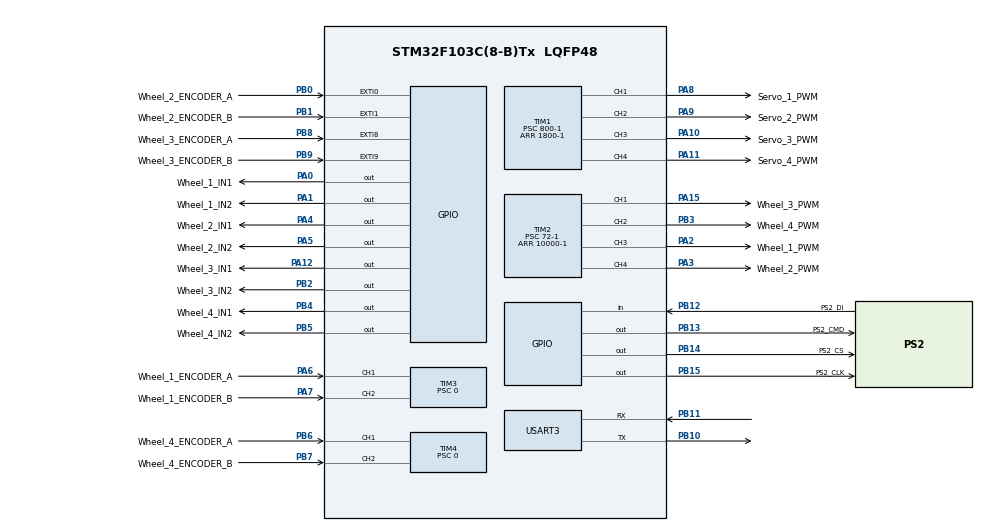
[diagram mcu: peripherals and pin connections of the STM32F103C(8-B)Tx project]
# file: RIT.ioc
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Dma.Request0=USART3_RX
Dma.Request1=USART3_TX
Dma.USART3_RX.0.Direction=DMA_PERIPH_TO_MEMORY
Dma.USART3_RX.0.Instance=DMA1_Channel3
Dma.USART3_RX.0.MemDataAlignment=DMA_MDATAALIGN_BYTE
Dma.USART3_RX.0.MemInc=DMA_MINC_ENABLE
Dma.USART3_RX.0.Mode=DMA_NORMAL
Dma.USART3_RX.0.PeriphDataAlignment=DMA_PDATAALIGN_BYTE
Dma.USART3_RX.0.PeriphInc=DMA_PINC_DISABLE
Dma.USART3_RX.0.Priority=DMA_PRIORITY_LOW
Dma.USART3_TX.1.Direction=DMA_MEMORY_TO_PERIPH
Dma.USART3_TX.1.Instance=DMA1_Channel2
Dma.USART3_TX.1.MemDataAlignment=DMA_MDATAALIGN_BYTE
Dma.USART3_TX.1.MemInc=DMA_MINC_ENABLE
Dma.USART3_TX.1.Mode=DMA_NORMAL
Dma.USART3_TX.1.PeriphDataAlignment=DMA_PDATAALIGN_BYTE
Dma.USART3_TX.1.PeriphInc=DMA_PINC_DISABLE
Dma.USART3_TX.1.Priority=DMA_PRIORITY_LOW
Mcu.Family=STM32F1
Mcu.Name=STM32F103C(8-B)Tx
Mcu.Package=LQFP48
NVIC.DMA1_Channel2_IRQn=true\:0\:0\:false\:false\:true\:false\:true\:true
NVIC.DMA1_Channel3_IRQn=true\:0\:0\:false\:false\:true\:false\:true\:true
NVIC.EXTI0_IRQn=true\:0\:0\:false\:false\:true\:true\:true\:true
NVIC.EXTI1_IRQn=true\:0\:0\:false\:false\:true\:true\:true\:true
NVIC.EXTI9_5_IRQn=true\:0\:0\:false\:false\:true\:true\:true\:true
NVIC.PriorityGroup=NVIC_PRIORITYGROUP_4
NVIC.TIM3_IRQn=true\:0\:0\:false\:false\:true\:true\:true\:true
NVIC.TIM4_IRQn=true\:0\:0\:false\:false\:true\:true\:true\:true
NVIC.USART3_IRQn=true\:0\:0\:false\:false\:true\:true\:true\:true
PA0-WKUP.GPIO_Label=Wheel_1_IN1
PA0-WKUP.Signal=GPIO_Output
PA1.GPIO_Label=Wheel_1_IN2
PA1.Signal=GPIO_Output
PA10.GPIO_Label=Servo_3_PWM
PA10.Signal=S_TIM1_CH3
PA11.GPIO_Label=Servo_4_PWM
PA11.Signal=S_TIM1_CH4
PA12.GPIO_Label=Wheel_3_IN1
PA12.Signal=GPIO_Output
PA13.Mode=Serial_Wire
PA13.Signal=SYS_JTMS-SWDIO
PA14.Mode=Serial_Wire
PA14.Signal=SYS_JTCK-SWCLK
PA15.GPIO_Label=Wheel_3_PWM
PA15.Signal=S_TIM2_CH1_ETR
PA2.GPIO_Label=Wheel_1_PWM
PA2.Signal=S_TIM2_CH3
PA3.GPIO_Label=Wheel_2_PWM
PA3.Signal=S_TIM2_CH4
PA4.GPIO_Label=Wheel_2_IN1
PA4.Signal=GPIO_Output
PA5.GPIO_Label=Wheel_2_IN2
PA5.Signal=GPIO_Output
PA6.GPIO_Label=Wheel_1_ENCODER_A
PA6.GPIO_PuPd=GPIO_PULLUP
PA6.Signal=S_TIM3_CH1
PA7.GPIO_Label=Wheel_1_ENCODER_B
PA7.GPIO_PuPd=GPIO_PULLUP
PA7.Signal=S_TIM3_CH2
PA8.GPIO_Label=Servo_1_PWM
PA8.Signal=S_TIM1_CH1
PA9.GPIO_Label=Servo_2_PWM
PA9.Signal=S_TIM1_CH2
PB0.GPIO_Label=Wheel_2_ENCODER_A
PB0.GPIO_ModeDefaultEXTI=GPIO_MODE_IT_RISING_FALLING
PB0.GPIO_PuPd=GPIO_PULLDOWN
PB0.Signal=GPXTI0
PB1.GPIO_Label=Wheel_2_ENCODER_B
PB1.GPIO_ModeDefaultEXTI=GPIO_MODE_IT_RISING_FALLING
PB1.GPIO_PuPd=GPIO_PULLDOWN
PB1.Signal=GPXTI1
PB10.Mode=Asynchronous
PB10.Signal=USART3_TX
PB11.Mode=Asynchronous
PB11.Signal=USART3_RX
PB12.GPIO_Label=PS2_DI
PB12.GPIO_PuPd=GPIO_PULLUP
PB12.Signal=GPIO_Input
PB13.GPIO_Label=PS2_CMD
PB13.GPIO_Speed=GPIO_SPEED_FREQ_HIGH
PB13.PinState=GPIO_PIN_SET
PB13.Signal=GPIO_Output
PB14.GPIO_Label=PS2_CS
PB14.GPIO_Speed=GPIO_SPEED_FREQ_HIGH
PB14.PinState=GPIO_PIN_SET
PB14.Signal=GPIO_Output
PB15.GPIO_Label=PS2_CLK
PB15.GPIO_Speed=GPIO_SPEED_FREQ_HIGH
PB15.PinState=GPIO_PIN_RESET
PB15.Signal=GPIO_Output
PB2.GPIO_Label=Wheel_3_IN2
PB2.Signal=GPIO_Output
PB3.GPIO_Label=Wheel_4_PWM
PB3.Signal=S_TIM2_CH2
PB4.GPIO_Label=Wheel_4_IN1
PB4.Signal=GPIO_Output
PB5.GPIO_Label=Wheel_4_IN2
PB5.Signal=GPIO_Output
PB6.GPIO_Label=Wheel_4_ENCODER_A
PB6.GPIO_PuPd=GPIO_PULLUP
PB6.Signal=S_TIM4_CH1
PB7.GPIO_Label=Wheel_4_ENCODER_B
PB7.GPIO_PuPd=GPIO_PULLUP
PB7.Signal=S_TIM4_CH2
PB8.GPIO_Label=Wheel_3_ENCODER_A
PB8.GPIO_ModeDefaultEXTI=GPIO_MODE_IT_RISING_FALLING
PB8.GPIO_PuPd=GPIO_PULLDOWN
PB8.Signal=GPXTI8
PB9.GPIO_Label=Wheel_3_ENCODER_B
PB9.GPIO_ModeDefaultEXTI=GPIO_MODE_IT_RISING_FALLING
PB9.GPIO_PuPd=GPIO_PULLDOWN
PB9.Signal=GPXTI9
PD0-OSC_IN.Mode=HSE-External-Oscillator
PD0-OSC_IN.Signal=RCC_OSC_IN
PD1-OSC_OUT.Mode=HSE-External-Oscillator
PD1-OSC_OUT.Signal=RCC_OSC_OUT
ProjectManager.HeapSize=0x200
ProjectManager.StackSize=0x400
ProjectManager.TargetToolchain=Makefile
RCC.AHBFreq_Value=72000000
RCC.APB1CLKDivider=RCC_HCLK_DIV2
RCC.APB1Freq_Value=36000000
RCC.APB1TimFreq_Value=72000000
RCC.APB2Freq_Value=72000000
RCC.APB2TimFreq_Value=72000000
RCC.HCLKFreq_Value=72000000
RCC.PLLMUL=RCC_PLL_MUL9
RCC.PLLSourceVirtual=RCC_PLLSOURCE_HSE
RCC.SYSCLKFreq_VALUE=72000000
RCC.SYSCLKSource=RCC_SYSCLKSOURCE_PLLCLK
RCC.USBFreq_Value=72000000
SH.S_TIM1_CH1.0=TIM1_CH1,PWM Generation1 CH1
SH.S_TIM1_CH2.0=TIM1_CH2,PWM Generation2 CH2
SH.S_TIM1_CH3.0=TIM1_CH3,PWM Generation3 CH3
SH.S_TIM1_CH4.0=TIM1_CH4,PWM Generation4 CH4
SH.S_TIM2_CH1_ETR.0=TIM2_CH1,PWM Generation1 CH1
SH.S_TIM2_CH2.0=TIM2_CH2,PWM Generation2 CH2
SH.S_TIM2_CH3.0=TIM2_CH3,PWM Generation3 CH3
SH.S_TIM2_CH4.0=TIM2_CH4,PWM Generation4 CH4
SH.S_TIM3_CH1.0=TIM3_CH1,Encoder_Interface
SH.S_TIM3_CH2.0=TIM3_CH2,Encoder_Interface
SH.S_TIM4_CH1.0=TIM4_CH1,Encoder_Interface
SH.S_TIM4_CH2.0=TIM4_CH2,Encoder_Interface
TIM1.AutoReloadPreload=TIM_AUTORELOAD_PRELOAD_ENABLE
TIM1.Channel-PWM\ Generation1\ CH1=TIM_CHANNEL_1
TIM1.Channel-PWM\ Generation2\ CH2=TIM_CHANNEL_2
TIM1.Channel-PWM\ Generation3\ CH3=TIM_CHANNEL_3
TIM1.Channel-PWM\ Generation4\ CH4=TIM_CHANNEL_4
TIM1.OCPolarity_3=TIM_OCPOLARITY_HIGH
TIM1.Period=1800-1
TIM1.Prescaler=800-1
TIM2.AutoReloadPreload=TIM_AUTORELOAD_PRELOAD_ENABLE
TIM2.Channel-PWM\ Generation1\ CH1=TIM_CHANNEL_1
TIM2.Channel-PWM\ Generation2\ CH2=TIM_CHANNEL_2
TIM2.Channel-PWM\ Generation3\ CH3=TIM_CHANNEL_3
TIM2.Channel-PWM\ Generation4\ CH4=TIM_CHANNEL_4
TIM2.OCPolarity_3=TIM_OCPOLARITY_HIGH
TIM2.OCPolarity_4=TIM_OCPOLARITY_HIGH
TIM2.Period=10000-1
TIM2.Prescaler=72-1
TIM3.AutoReloadPreload=TIM_AUTORELOAD_PRELOAD_DISABLE
TIM3.EncoderMode=TIM_ENCODERMODE_TI12
TIM3.Period=65535
TIM3.Prescaler=0
TIM4.AutoReloadPreload=TIM_AUTORELOAD_PRELOAD_DISABLE
TIM4.EncoderMode=TIM_ENCODERMODE_TI12
TIM4.Period=65535
TIM4.Prescaler=0
USART3.VirtualMode=VM_ASYNC
VP_TIM1_VS_ClockSourceINT.Mode=Internal
VP_TIM2_VS_ClockSourceINT.Mode=Internal
board=custom

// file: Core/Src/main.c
/* USER CODE BEGIN Header */
/**
 ******************************************************************************
 * @file           : main.c
 * @brief          : Main program body
 ******************************************************************************
 * @attention
 *
 * Copyright (c) 2025 STMicroelectronics.
 * All rights reserved.
 *
 * This software is licensed under terms that can be found in the LICENSE file
 * in the root directory of this software component.
 * If no LICENSE file comes with this software, it is provided AS-IS.
 *
 ******************************************************************************
 */
/* USER CODE END Header */
#include "main.h"
#include "dma.h"
#include "tim.h"
#include "usart.h"
#include "gpio.h"

/* USER CODE BEGIN Includes */
#include "crc.h"
#include "wheel.h"
#include "servo.h"
#include "ax_ps2.h"
/* USER CODE END Includes */

/* USER CODE BEGIN PD */
#define UART_RX_BUFF_LENGTH 64
/* USER CODE END PD */

/* USER CODE BEGIN PV */
uint8_t UART_RxBuff[UART_RX_BUFF_LENGTH];
/* USER CODE END PV */

void SystemClock_Config(void);

int main(void)
{

    /* MCU Configuration--------------------------------------------------------*/

    /* Reset of all peripherals, Initializes the Flash interface and the Systick. */
    HAL_Init();

    /* USER CODE BEGIN Init */
    // 手柄配置
    AX_PS2_Init();
    /* USER CODE END Init */

    /* Configure the system clock */
    SystemClock_Config();

    /* Initialize all configured peripherals */
    MX_GPIO_Init();
    MX_DMA_Init();
    MX_TIM1_Init();
    MX_TIM4_Init();
    MX_TIM2_Init();
    MX_TIM3_Init();
    MX_USART3_UART_Init();
    /* USER CODE BEGIN 2 */
    // CRC 配置
    crc8_init_table();
    // 车轮配置
    HAL_TIM_Encoder_Start(&htim3, TIM_CHANNEL_ALL);
    __HAL_TIM_SetCounter(&htim3, 32767);
    HAL_TIM_Encoder_Start(&htim4, TIM_CHANNEL_ALL);
    __HAL_TIM_SetCounter(&htim4, 32767);
    Wheel_Init();
    // 舵机配置
    Servo_Init();

    // 串口接受数据开始
    HAL_UARTEx_ReceiveToIdle_DMA(&huart3, UART_RxBuff, UART_RX_BUFF_LENGTH);
    /* USER CODE END 2 */

    /* Infinite loop */
    while (1) {

    }
}

void SystemClock_Config(void)
{
    RCC_OscInitTypeDef RCC_OscInitStruct = {0};
    RCC_ClkInitTypeDef RCC_ClkInitStruct = {0};

    /** Initializes the RCC Oscillators according to the specified parameters
     * in the RCC_OscInitTypeDef structure.
     */
    RCC_OscInitStruct.OscillatorType      = RCC_OSCILLATORTYPE_HSI;
    RCC_OscInitStruct.HSIState            = RCC_HSI_ON;
    RCC_OscInitStruct.HSICalibrationValue = RCC_HSICALIBRATION_DEFAULT;
    RCC_OscInitStruct.PLL.PLLState        = RCC_PLL_ON;
    RCC_OscInitStruct.PLL.PLLSource       = RCC_PLLSOURCE_HSI_DIV2;
    RCC_OscInitStruct.PLL.PLLMUL          = RCC_PLL_MUL9;
    if (HAL_RCC_OscConfig(&RCC_OscInitStruct) != HAL_OK) {
        Error_Handler();
    }

    /** Initializes the CPU, AHB and APB buses clocks
     */
    RCC_ClkInitStruct.ClockType      = RCC_CLOCKTYPE_HCLK | RCC_CLOCKTYPE_SYSCLK | RCC_CLOCKTYPE_PCLK1 | RCC_CLOCKTYPE_PCLK2;
    RCC_ClkInitStruct.SYSCLKSource   = RCC_SYSCLKSOURCE_PLLCLK;
    RCC_ClkInitStruct.AHBCLKDivider  = RCC_SYSCLK_DIV1;
    RCC_ClkInitStruct.APB1CLKDivider = RCC_HCLK_DIV2;
    RCC_ClkInitStruct.APB2CLKDivider = RCC_HCLK_DIV1;

    if (HAL_RCC_ClockConfig(&RCC_ClkInitStruct, FLASH_LATENCY_1) != HAL_OK) {
        Error_Handler();
    }
}

/* USER CODE BEGIN 4 */

Wheel_Control_Data wheel_control_data;
Car_Go_Straight_Data car_go_straight_data;
Car_Spin_Data car_spin_data;
Car_Gear_Select_Data car_gear_select_data;

float car_gear[4] = {0.0f, 1.0f, 1.5f, 2.0f};

/**
 * @brief  Reception Event Callback (Rx event notification called after use of advanced reception service).
 * @param  huart UART handle
 * @param  Size  Number of data available in application reception buffer (indicates a position in
 *               reception buffer until which, data are available)
 * @retval None
 */
void HAL_UARTEx_RxEventCallback(UART_HandleTypeDef *huart, uint16_t Size)
{
    if (huart->Instance == USART3) {
        // UART不定长数据接受中断处理代码
        switch (UART_RxBuff[0]) {
            case WHEEL_CONTROL:
                WheelControlDataInit(&wheel_control_data, UART_RxBuff);
                CarMove(wheel_control_data.Vx, wheel_control_data.Vy, wheel_control_data.Vz);
                break;
            case SERVO_CONTROL:
                ServoControlDataInit(&servo_data, UART_RxBuff);
                UpdateServoAngle();
                break;
            case CAR_GO_STRAIGHT:
                CarGoStraightDataInit(&car_go_straight_data, UART_RxBuff);
                CarGoStraight(car_go_straight_data.angle);
                break;
            case CAR_SPIN:
                CarSpinDataInit(&car_spin_data, UART_RxBuff);
                CarSpin(car_spin_data.direction);
                break;
            case CAR_GEAR_SELECT:
                CarGearSelectDataInit(&car_gear_select_data, UART_RxBuff);
                if (car_gear_select_data.gear > 3) {
                    car_gear_select_data.gear = 3;
                }
                max_speed = car_gear[car_gear_select_data.gear];
                break;
            default:
                break;
        }

        // 开始接受下一组数据
        HAL_UARTEx_ReceiveToIdle_DMA(&huart3, UART_RxBuff, UART_RX_BUFF_LENGTH);
    }
}

/**
 * @brief  EXTI line detection callbacks.
 * @param  GPIO_Pin: Specifies the pins connected EXTI line
 * @retval None
 */
void HAL_GPIO_EXTI_Callback(uint16_t GPIO_Pin)
{
    switch (GPIO_Pin) {
        case GPIO_PIN_0:
            WHEEL_PULSE[WHEEL_LB - 1]++;
            break;
        case GPIO_PIN_1:
            WHEEL_PULSE[WHEEL_LB - 1]++;
            break;
        case GPIO_PIN_8:
            WHEEL_PULSE[WHEEL_RF - 1]++;
            break;
        case GPIO_PIN_9:
            WHEEL_PULSE[WHEEL_RF - 1]++;
            break;
        default:
            break;
    }
}

/* USER CODE END 4 */

void Error_Handler(void)
{
    __disable_irq();
    while (1) {
    }
}
